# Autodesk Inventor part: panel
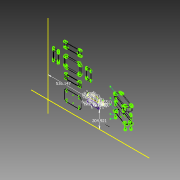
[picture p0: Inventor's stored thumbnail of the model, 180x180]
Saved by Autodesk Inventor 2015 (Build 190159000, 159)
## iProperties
Created: 2017-03
Part Number: panel
Material: Generic
Document SubType Name: Modeling
Designer: Braciszek
Density: 1 g/cm^3
Appearance: Default
Author: takachi
部品番号: pf20-6-13
設計者: takachi
設計ステータス: 作業中
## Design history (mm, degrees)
sketch "Sketch1"
  geometry: L1 (823.502, 461.601)-(828.987, 458.606); L2 (822.903, 460.504)-(828.987, 458.606); L3 (828.987, 458.606)-(824.101, 462.699); L4 (823.502, 461.601)-(750.065, 501.696); L5 (808.525, 358.251)-(814.224, 355.687); L6 (808.012, 357.111)-(814.224, 355.687); L7 (814.224, 355.687)-(809.038, 359.391); L8 (808.525, 358.251)-(750.308, 384.447); L9 (816.367, 294.98)-(822.239, 292.838); L10 (815.939, 293.806)-(822.239, 292.838); L11 (822.239, 292.838)-(816.796, 296.154); L12 (816.367, 294.98)-(750.539, 318.994); L13 (794.845, 243.637)-(800.681, 245.874); L14 (795.292, 242.47)-(800.681, 245.874); L15 (800.681, 245.874)-(794.397, 244.804); L16 (794.845, 243.637)-(750.488, 226.639); L17 (793.669, 207.441)-(798.772, 211.05); L18 (794.391, 206.42)-(798.772, 211.05); L19 (798.772, 211.05)-(792.947, 208.462); L20 (793.669, 207.441)-(749.594, 176.268); C1 r 7.5 at (743.494, 505.284); C2 r 7.5 at (743.494, 387.513); C3 r 7.5 at (743.494, 321.564); C4 r 7.5 at (743.494, 223.959); C5 r 7.5 at (743.494, 171.953); 7 further points
  constraints: 40 end point, 5 centre point, 6 other
sketch "Tweak Trail (ISO)"
  geometry: L1 (802.661, 264.468)-(802.661, 251.262); L2 (940.491, 316.686)-(940.402, 319.602); L3 (985.801, 260.354)-(985.801, 259.642); L4 (917.212, 204.468)-(917.212, 185.126); L5 (917.212, 220.753)-(917.212, 220.042); L6 (802.661, 264.468)-(802.661, 251.262); L7 (802.661, 286.89)-(802.661, 286.178); L8 (985.801, 215.325)-(985.801, 191.25); L9 (985.801, 237.932)-(985.801, 224.726); L10 (917.212, 175.725)-(917.212, 151.65); L11 (917.212, 204.468)-(917.212, 185.126); L12 (847.971, 263.287)-(849.594, 317.899); L13 (894.238, 334.723)-(894.238, 346.585); L14 (985.801, 237.932)-(985.801, 224.726); L15 (802.661, 241.861)-(802.661, 217.786)
  constraints: 30 end point
sketch "Visible (ISO)"
  geometry: L1 (361.379, 564.87)-(361.364, 564.87); L2 (227.43, 564.87)-(227.415, 564.87); L3 (227.415, 430.87)-(227.43, 430.87); L4 (361.364, 430.87)-(361.379, 430.87); L5 (918.712, 178.594)-(918.712, 183.248); L6 (361.897, 430.37)-(226.897, 430.37); L7 (226.897, 565.37)-(361.897, 565.37); L8 (914.56, 177.164)-(914.417, 178.494); L9 (919.864, 177.164)-(920.007, 178.494); L10 (214.248, 536.553)-(214.249, 537.225); L11 (214.249, 537.225)-(214.478, 539.24); L12 (214.478, 539.24)-(215.97, 542.332); L13 (215.97, 542.332)-(219.188, 544.899); L14 (219.188, 544.899)-(221.869, 545.516); L15 (221.869, 545.516)-(223.214, 545.519); L16 (986.955, 224.796)-(987.293, 222.939); L17 (984.648, 224.796)-(984.31, 222.939); L18 (984.301, 218.194)-(984.301, 222.848); L19 (987.301, 218.194)-(987.301, 222.848); L20 (983.15, 216.764)-(983.007, 218.094); L21 (810.216, 461.912)-(864.898, 493.482); L22 (799.677, 212.132)-(799.65, 212.156); L23 (799.65, 212.156)-(799.627, 212.182); L24 (799.627, 212.182)-(799.594, 212.236); L25 (799.594, 212.236)-(799.583, 212.264); L26 (799.583, 212.264)-(799.576, 212.303); L27 (799.576, 212.303)-(799.575, 212.315); L28 (799.575, 212.315)-(799.575, 212.329); L29 (223.214, 450.22)-(221.869, 450.223); L30 (221.869, 450.223)-(219.188, 450.84); L31 (219.188, 450.84)-(215.97, 453.407); L32 (215.97, 453.407)-(214.478, 456.499); L33 (214.478, 456.499)-(214.249, 458.514); L34 (214.249, 458.514)-(214.248, 459.187); L35 (801.536, 211.728)-(801.506, 211.686); L36 (801.506, 211.686)-(801.462, 211.648); L37 (801.462, 211.648)-(801.407, 211.616); L38 (801.407, 211.616)-(801.354, 211.586); L39 (801.354, 211.586)-(801.293, 211.561); L40 (801.293, 211.561)-(801.225, 211.544); L41 (801.225, 211.544)-(801.222, 211.543); L42 (801.222, 211.543)-(801.218, 211.542); L43 (801.218, 211.542)-(801.215, 211.541); L44 (801.215, 211.541)-(801.143, 211.523); L45 (801.143, 211.523)-(801.065, 211.514); L46 (801.065, 211.514)-(800.987, 211.514); L47 (800.987, 211.514)-(800.968, 211.514); L48 (800.968, 211.514)-(800.948, 211.514); L49 (800.948, 211.514)-(800.929, 211.515); L50 (800.929, 211.515)-(800.888, 211.517); L51 (800.888, 211.517)-(800.848, 211.522); L52 (800.848, 211.522)-(800.809, 211.528); L53 (800.809, 211.528)-(800.751, 211.538); L54 (800.751, 211.538)-(800.696, 211.553); L55 (800.696, 211.553)-(800.646, 211.573); L56 (800.104, 216.518)-(800.123, 216.523); L57 (800.123, 216.523)-(800.145, 216.521); L58 (800.145, 216.521)-(800.207, 216.501); L59 (800.207, 216.501)-(800.25, 216.473); L60 (800.25, 216.473)-(800.293, 216.437); L61 (800.293, 216.437)-(800.294, 216.437); L62 (800.294, 216.437)-(800.294, 216.437); L63 (801.031, 216.011)-(801.031, 216.011); L64 (801.031, 216.011)-(801.031, 216.011)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; C1 r 0.95 at (296.783, 113.336); C2 r 1.25 at (296.783, 113.336); C3 r 2.3 at (296.783, 113.336); C4 r 0.95 at (296.783, 191.336); C5 r 1.25 at (296.783, 191.336); C6 r 2.3 at (296.783, 191.336); C7 r 2.326 at (296.783, 191.336); C8 r 2.326 at (296.783, 113.336); C9 r 4.855 at (377.783, 103.836); C10 r 4.855 at (377.783, 200.836); C11 r 4.855 at (215.783, 200.836); C12 r 4.855 at (215.783, 103.836); C13 r 3.05 at (225.283, 113.336); C14 r 3.05 at (368.283, 113.336); C15 r 3.05 at (368.283, 191.336); C16 r 3.05 at (225.283, 191.336); C17 r 2.68 at (368.283, 113.336); C18 r 2.3 at (368.283, 113.336); C19 r 2.68 at (368.283, 191.336); C20 r 2.3 at (368.283, 191.336); C21 r 2.68 at (225.283, 191.336); C22 r 2.3 at (225.283, 191.336); C23 r 2.68 at (225.283, 113.336); C24 r 2.3 at (225.283, 113.336); C25 r 0.95 at (368.283, 113.336); C26 r 1.25 at (368.283, 113.336); C27 r 0.95 at (225.283, 113.336); C28 r 1.25 at (225.283, 113.336); C29 r 0.95 at (225.283, 191.336); C30 r 1.25 at (225.283, 191.336); C31 r 0.95 at (368.283, 191.336); C32 r 1.25 at (368.283, 191.336); C33 r 3.85 at (377.783, 103.836); C34 r 1.75 at (377.783, 103.836); C35 r 3.85 at (377.783, 200.836); C36 r 1.75 at (377.783, 200.836); C37 r 3.85 at (215.783, 103.836); C38 r 1.75 at (215.783, 103.836); C39 r 3.85 at (215.783, 200.836); C40 r 1.75 at (215.783, 200.836); A1 r 25 centre (367.397, 537.87) between (391.885, 542.904) and (391.867, 542.989); A2 r 25 centre (221.397, 537.87) between (196.927, 542.989) and (196.909, 542.905); A3 r 25 centre (221.397, 457.87) between (208.586, 436.401) and (208.617, 436.383); A4 r 25 centre (367.397, 457.87) between (391.867, 452.75) and (391.885, 452.834); A5 r 0.6 centre (800.196, 215.924) between (800.057, 216.507) and (799.596, 215.927); A6 r 0.6 centre (800.196, 217.852) between (799.807, 218.309) and (799.596, 217.856); A7 r 0.6 centre (800.99, 218.311) between (800.982, 218.911) and (800.772, 218.869); A8 r 0.6 centre (804.331, 218.311) between (804.549, 218.869) and (804.339, 218.911); A9 r 0.6 centre (805.125, 217.852) between (805.725, 217.856) and (805.514, 218.309); A10 r 0.6 centre (805.125, 215.924) between (805.725, 215.927) and (805.265, 216.507); A11 r 0.6 centre (914.748, 149.787) between (914.608, 150.371) and (914.148, 149.791); A12 r 0.6 centre (914.748, 151.716) between (914.359, 152.173) and (914.148, 151.72); A13 r 0.6 centre (915.542, 152.174) between (915.534, 152.774) and (915.323, 152.733); A14 r 0.6 centre (918.882, 152.174) between (919.101, 152.733) and (918.89, 152.774); A15 r 0.6 centre (919.676, 151.716) between (920.276, 151.72) and (920.065, 152.173); A16 r 0.6 centre (919.676, 149.787) between (920.276, 149.791) and (919.816, 150.371); A17 r 1 centre (197.164, 639.565) between (196.164, 639.53) and (197.081, 638.569); A18 r 1 centre (391.63, 639.565) between (391.713, 638.569) and (392.629, 639.53); A19 r 10 centre (350.552, 653.143) between (350.552, 643.143) and (360.546, 652.782); A20 r 10 centre (238.242, 653.143) between (228.248, 652.782) and (238.242, 643.143); A21 r 50.021 centre (212.922, 649.125) between (212.922, 699.145) and (208.428, 698.943); A22 r 50.021 centre (213.872, 649.125) between (218.365, 698.943) and (213.872, 699.145); A23 r 0.6 centre (983.337, 189.388) between (983.198, 189.971) and (982.737, 189.391); A24 r 50.021 centre (374.922, 649.125) between (374.922, 699.145) and (370.428, 698.943); A25 r 50.021 centre (375.872, 649.125) between (380.366, 698.943) and (375.872, 699.145); A26 r 0.6 centre (983.337, 191.316) between (982.948, 191.773) and (982.737, 191.32); A27 r 0.6 centre (984.131, 191.775) between (984.123, 192.375) and (983.913, 192.333); A28 r 0.6 centre (987.472, 191.775) between (987.69, 192.333) and (987.48, 192.375); A29 r 0.6 centre (988.266, 191.316) between (988.866, 191.32) and (988.655, 191.773); A30 r 0.6 centre (988.266, 189.388) between (988.866, 189.391) and (988.405, 189.971); A31 r 1 centre (121.462, 562.603) between (122.459, 562.686) and (121.497, 563.602); A32 r 1 centre (121.462, 433.136) between (121.497, 432.137) and (122.459, 433.054); A33 r 50.021 centre (111.903, 448.895) between (61.882, 448.895) and (62.084, 444.401); A34 r 50.021 centre (111.903, 449.845) between (62.084, 454.338) and (61.882, 449.845); A35 r 50.021 centre (111.903, 545.895) between (61.882, 545.895) and (62.084, 541.401); A36 r 50.021 centre (111.903, 546.845) between (62.084, 551.338) and (61.882, 546.845); A37 r 0.3 centre (512.465, 454.557) between (512.467, 454.257) and (512.765, 454.557); A38 r 0.3 centre (512.465, 444.182) between (512.765, 444.182) and (512.467, 444.482); A39 r 0.3 centre (512.465, 551.557) between (512.467, 551.257) and (512.765, 551.557); A40 r 0.3 centre (512.465, 541.182) between (512.765, 541.182) and (512.467, 541.482); A41 r 0.1 centre (510.261, 563.92) between (510.361, 563.923) and (510.261, 564.02); A42 r 0.1 centre (510.312, 562.47) between (510.312, 562.37) and (510.412, 562.473); A43 r 0.5 centre (512.265, 560.747) between (512.765, 560.747) and (512.283, 561.247); A44 r 0.5 centre (512.265, 434.992) between (512.283, 434.492) and (512.765, 434.992); A45 r 0.1 centre (510.312, 433.27) between (510.412, 433.266) and (510.312, 433.37); A46 r 0.1 centre (510.261, 431.82) between (510.261, 431.72) and (510.361, 431.816); A47 r 0.3 centre (513.065, 540.22) between (512.769, 540.175) and (513.065, 539.92); A48 r 0.37 centre (513.145, 539.55) between (513.515, 539.55) and (513.145, 539.92); A49 r 0.37 centre (513.146, 539.568) between (513.148, 539.198) and (513.515, 539.55); A50 r 0.37 centre (513.146, 534.171) between (513.515, 534.19) and (513.148, 534.541); A51 r 0.37 centre (513.145, 534.19) between (513.145, 533.82) and (513.515, 534.19); A52 r 0.3 centre (513.065, 533.52) between (513.065, 533.82) and (512.765, 533.52); A53 r 0.3 centre (513.065, 462.22) between (512.765, 462.22) and (513.065, 461.92); A54 r 0.37 centre (513.145, 461.55) between (513.515, 461.55) and (513.145, 461.92); A55 r 0.37 centre (513.146, 461.568) between (513.148, 461.198) and (513.515, 461.55); A56 r 0.37 centre (513.146, 456.171) between (513.515, 456.19) and (513.148, 456.541); A57 r 0.37 centre (513.145, 456.19) between (513.145, 455.82) and (513.515, 456.19); A58 r 0.3 centre (513.065, 455.52) between (513.065, 455.82) and (512.765, 455.52); A59 r 0.3 centre (458.465, 455.52) between (458.765, 455.52) and (458.465, 455.82); A60 r 0.37 centre (458.385, 456.19) between (458.015, 456.19) and (458.385, 455.82); A61 r 0.37 centre (458.385, 456.171) between (458.383, 456.541) and (458.015, 456.19); A62 r 0.37 centre (458.385, 461.568) between (458.015, 461.55) and (458.383, 461.198); A63 r 0.37 centre (458.385, 461.55) between (458.385, 461.92) and (458.015, 461.55); A64 r 0.3 centre (458.465, 462.22) between (458.465, 461.92) and (458.765, 462.22)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; 526 further points; 190 other entities
  constraints: 1982 end point, 360 point on circle, 220 centre point, 1196 other
  dimensions: "d0" = 9.4546 radius of A170
sketch "Visible Narrow (ISO)"
  geometry: L1 (222.497, 432.145)-(222.497, 432.145); L2 (197.081, 536.619)-(197.081, 540.518); L3 (197.081, 540.518)-(198.859, 548.315); L4 (198.859, 548.315)-(206.338, 557.699); L5 (206.338, 557.699)-(215.347, 562.033); L6 (215.347, 562.033)-(221.198, 562.685); L7 (221.198, 562.685)-(223.148, 562.686); L8 (223.148, 563.602)-(221.13, 563.602); L9 (221.13, 563.602)-(215.073, 562.926); L10 (215.073, 562.926)-(205.747, 558.44); L11 (205.747, 558.44)-(198.005, 548.726); L12 (198.005, 548.726)-(196.165, 540.655); L13 (196.165, 540.655)-(196.164, 536.619); L14 (197.081, 536.586)-(197.081, 536.619); L15 (197.081, 536.586)-(214.248, 536.553); L16 (223.214, 545.519)-(223.181, 562.686); L17 (223.148, 562.686)-(223.181, 562.686); L18 (223.148, 433.054)-(219.248, 433.054); L19 (219.248, 433.054)-(211.452, 434.831); L20 (211.452, 434.831)-(202.067, 442.31); L21 (202.067, 442.31)-(197.734, 451.319); L22 (197.734, 451.319)-(197.081, 457.171); L23 (197.081, 457.171)-(197.081, 459.121); L24 (196.164, 459.121)-(196.164, 457.102); L25 (196.164, 457.102)-(196.84, 451.045); L26 (196.84, 451.045)-(201.327, 441.72); L27 (201.327, 441.72)-(211.041, 433.977); L28 (211.041, 433.977)-(219.111, 432.137); L29 (219.111, 432.137)-(223.148, 432.137); L30 (223.181, 433.054)-(223.148, 433.054); L31 (223.181, 433.054)-(223.214, 450.22); L32 (214.248, 459.186)-(197.081, 459.153); L33 (197.081, 459.121)-(197.081, 459.153); L34 (391.713, 459.121)-(391.713, 455.221); L35 (391.713, 455.221)-(389.935, 447.424); L36 (389.935, 447.424)-(382.456, 438.04); L37 (382.456, 438.04)-(373.447, 433.706); L38 (373.447, 433.706)-(367.596, 433.054); L39 (367.596, 433.054)-(365.646, 433.054); L40 (365.646, 432.137)-(367.664, 432.137); L41 (367.664, 432.137)-(373.721, 432.813); L42 (373.721, 432.813)-(383.047, 437.299); L43 (383.047, 437.299)-(390.789, 447.013); L44 (390.789, 447.013)-(392.629, 455.084); L45 (392.629, 455.084)-(392.63, 459.121); L46 (391.713, 459.153)-(391.713, 459.121); L47 (391.713, 459.153)-(374.546, 459.186); L48 (365.58, 450.22)-(365.613, 433.054); L49 (365.646, 433.054)-(365.613, 433.054); L50 (365.646, 562.686)-(367.596, 562.685); L51 (367.596, 562.685)-(373.447, 562.033); L52 (373.447, 562.033)-(382.456, 557.699); L53 (382.456, 557.699)-(389.935, 548.315); L54 (389.935, 548.315)-(391.713, 540.518); L55 (391.713, 540.518)-(391.713, 536.619); L56 (392.63, 536.619)-(392.629, 540.655); L57 (392.629, 540.655)-(390.789, 548.726); L58 (390.789, 548.726)-(383.047, 558.44); L59 (383.047, 558.44)-(373.721, 562.926); L60 (373.721, 562.926)-(367.664, 563.602); L61 (367.664, 563.602)-(365.646, 563.602); L62 (365.613, 562.686)-(365.646, 562.686); L63 (365.613, 562.686)-(365.58, 545.519); L64 (374.546, 536.553)-(391.713, 536.586)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; 576 further points; 192 other entities
  constraints: 596 end point, 855 other
sketch "panel"
  geometry: L1 (469.191, 269.762)-(470.556, 307.096) reference; L2 (603.099, 269.762)-(469.191, 269.762) reference; L3 (592.286, 316.251)-(480.004, 316.251) reference; L4 (467.608, 268.251)-(601.101, 268.251) reference; L5 (468.512, 307.171)-(467.144, 269.756) reference; L6 (592.286, 318.251)-(480.004, 318.251) reference; L7 (601.735, 307.096)-(603.099, 269.762) reference; L8 (605.146, 269.756)-(603.779, 307.171) reference; L9 (536.147, 252.921)-(536.147, 206.433); L10 (470.521, 243.768)-(469.192, 206.433); L11 (469.192, 206.433)-(603.101, 206.433); L12 (603.101, 206.433)-(601.772, 243.768); L13 (480.006, 252.921)-(592.288, 252.921); L14 (468.522, 243.839)-(467.156, 205.439); L15 (467.655, 204.921)-(601.056, 204.921); L16 (601.201, 268.351)-(601.201, 268.651) reference; L17 (601.201, 268.651)-(605.083, 268.651) reference; L18 (601.156, 205.021)-(601.156, 205.321); L19 (601.156, 205.321)-(605.038, 205.321); L20 (605.138, 205.425)-(603.771, 243.839); L21 (592.288, 254.921)-(480.006, 254.921); L22 (468.005, 229.296)-(470.003, 229.225); L23 (0, -139.839)-(0, 839.035) reference; L24 (-200.624, 0)-(1203.746, 0) reference; L25 (653.334, 316.205)-(653.334, 269.762) reference; L26 (655.434, 271.225)-(655.434, 314.776) reference; L27 (653.334, 269.762)-(654.634, 269.751) reference; L28 (654.783, 268.251)-(656.034, 268.251) reference; L29 (656.134, 268.351)-(656.134, 271.201) reference; L30 (656.134, 271.201)-(655.434, 271.225) reference; L31 (654.634, 269.751)-(654.683, 268.347) reference; L32 (656.134, 307.045)-(656.134, 271.201) reference; L33 (600.31, 243.716)-(601.585, 207.896); L34 (601.585, 207.896)-(470.708, 207.896); L35 (470.708, 207.896)-(471.983, 243.716); L36 (480.006, 251.458)-(592.288, 251.458); L37 (655.434, 271.225)-(653.334, 271.225); L38 (653.334, 271.225)-(653.334, 269.762); A1 r 9.5 centre (480.004, 306.751) between (480.004, 316.251) and (470.511, 307.098) reference; A2 r 9.491 centre (480.006, 243.43) between (480.006, 252.921) and (470.521, 243.768); A3 r 9.491 centre (592.288, 243.43) between (601.772, 243.768) and (592.288, 252.921); A4 r 0.1 centre (601.101, 268.351) between (601.101, 268.251) and (601.201, 268.351) reference; A5 r 0.1 centre (605.083, 268.751) between (605.083, 268.651) and (605.183, 268.755) reference; A6 r 0.1 centre (601.056, 205.021) between (601.056, 204.921) and (601.156, 205.021); A7 r 0.1 centre (605.038, 205.421) between (605.038, 205.321) and (605.138, 205.425); A8 r 11.491 centre (592.288, 243.43) between (603.771, 243.839) and (592.288, 254.921); A9 r 11.491 centre (480.006, 243.43) between (480.006, 254.921) and (468.522, 243.839); A10 r 0.5 centre (467.655, 205.421) between (467.156, 205.439) and (467.655, 204.921); A11 r 0.5 centre (467.608, 268.751) between (467.108, 268.769) and (467.608, 268.251) reference; A12 r 8.028 centre (592.288, 243.43) between (600.31, 243.716) and (592.288, 251.458); A13 r 8.028 centre (480.006, 243.43) between (480.006, 251.458) and (471.983, 243.716); 1 further point
  constraints: 36 end point, 18 point on circle, 10 tangent, 9 centre point, 6 equal length, 5 horizontal, 4 equal radius, 3 point on line, 3 vertical, 2 midpoint, 2 perpendicular, 2 symmetric about line, 1 parallel, 7 other
  dimensions: "d1" = 1.51135 distance between parallel lines of L2 L4 (derived); "d2" = 2.0454 distance between parallel lines of L1 L5 (derived); "d3" = 2.0454 distance between parallel lines of L8 L7 (derived); "d4" = 2 distance between parallel lines of L6 L3 (derived); "d5" = 46.48866 distance between parallel lines of L2 L3 (derived); "d6" = 46.48866 distance of L9.start L9.end (= d5); "d7" = 2 distance between parallel lines of L21 L13 (= d4); "d8" = 1.51135 distance between parallel lines of L11 L15 (= d1); "d10" = 0 distance of A9.centre A2.centre; "d11" = 0.5 radius of A10 (derived); "d12" = 0.5 radius of A11 (derived); "d16" = 204.9212 distance between parallel lines of L24 L15; "d17" = 536.14657 distance between parallel lines of L23 L9; "d18" = 0 distance of A2.centre A9.centre; "d20" = 1.4631 distance between parallel lines of L13 L36 (derived); "d21" = 43.55112 distance of L26.start L26.end (derived); "d22" = 1.4631 distance of L37.end L27.start (derived); "d23" = 0.7 horizontal distance of L30.start L30.end (derived); "d24" = 1.3 horizontal distance of L27.start L27.end (derived); "d25" = 2.8 distance between parallel lines of L32 L25 (derived)
extrude "Extrusion1" new body sketch "panel" distance "d26" = 2.8 (derived); taper "d27" = 0 deg
extrude "Extrusion2" join sketch "panel" distance "d28" = 1.5 (derived); taper "d29" = 0 deg
extrude "Extrusion4" cut sketch "panel" distance "d32" = 0.7 (derived); taper "d33" = 0 deg
body "Solid1"
other parameters: "d0" = 9.4546
